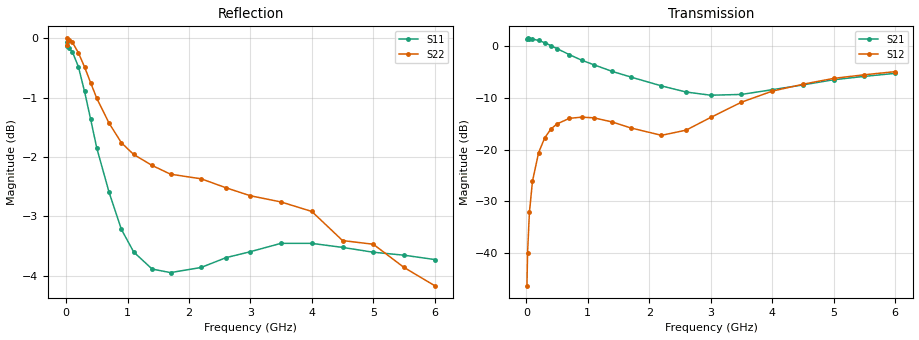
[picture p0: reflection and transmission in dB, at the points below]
! Infineon Technologies  Discrete & RF Semiconductors
! BFS17W
! Si NPN RF Bipolar Junction Transistor in SOT323
! VCE = 2 V  IC = 0.3 mA
! Common Emitter S-Parameters:  August  1999
# GHz  S  MA  R  50
!  f  S11  S21  S12  S22
! GHz  MAG  ANG  MAG  ANG  MAG  ANG  MAG  ANG
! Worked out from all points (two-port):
!   36 points, 10 MHz to 6 GHz, reference 50 ohm
!   highest |S21| = 1.58 dB at 20 MHz (marker M1); lowest = -9.4 dB at 3 GHz (marker M2)
!   |S21| within 3 dB of the highest: start of sweep to 671.9 MHz
!   lowest |S11| = -3.9 dB at 1.7 GHz (marker M3), VSWR 4.48, Z = 11.2 - j2.49 ohm
!   |S11| at or under -10 dB: nowhere
!   |S22| runs from -4.2 to 0.0 dB; largest |S21 - S12| = 1.2
!   S11 on the Smith chart (normalised r, x): 10 MHz: 27, -54; 300 MHz: 0.27, -2.04; 700 MHz: 0.24, -0.76; 1.4 GHz: 0.23, -0.19; 3 GHz: 0.24, +0.39; 6 GHz: 0.49, +1.09
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0.01  0.9852 -1.7  1.192 179.3  0.0048 86.8  0.9999 -0.1
0.02  0.9938 -3.8  1.199 176.9  0.0099 91.1  0.988 -1.1
0.05  0.9806 -9.1  1.195 172.2  0.0246 84.7  0.9971 -2.8
0.1  0.9746 -17.7  1.182 164.7  0.0494 79.0  0.9929 -5.6
0.2  0.9465 -35.4  1.144 149.2  0.0936 68.1  0.9723 -10.9
0.3  0.9022 -51.6  1.087 135.1  0.1304 58.2  0.946 -15.6
0.4  0.8545 -66.5  1.019 121.9  0.1585 49.4  0.9174 -19.8
0.5  0.808 -80.1  0.954 110.6  0.1776 42.0  0.89 -23.4
0.7  0.7418 -103.5  0.834 91.3  0.2012 30.8  0.8482 -29.8
0.9  0.6904 -122.5  0.737 76.2  0.2065 22.4  0.8167 -35.7
1.1  0.6608 -138.5  0.665 63.7  0.2035 16.7  0.7983 -41.5
1.4  0.6393 -157.9  0.573 49.4  0.1853 11.9  0.7815 -50.5
1.7  0.6349 -174.0  0.506 39.0  0.1624 12.7  0.7684 -60.1
2.2  0.6413 164.0  0.415 28.7  0.1377 28.9  0.7615 -76.4
2.6  0.6535 149.0  0.362 26.5  0.1545 47.8  0.7485 -90.0
3  0.6612 135.6  0.337 29.3  0.2051 57.6  0.7369 -103.1
3.5  0.672 121.1  0.343 34.2  0.2882 58.5  0.7281 -119.9
4  0.6719 109.0  0.381 36.3  0.3688 53.1  0.7148 -137.2
4.5  0.6667 98.5  0.424 35.2  0.4305 46.2  0.6756 -152.8
5  0.6605 90.6  0.476 31.8  0.4905 39.5  0.6708 -166.0
5.5  0.6567 83.9  0.513 27.7  0.532 33.0  0.6413 -179.5
6  0.6512 78.6  0.549 23.1  0.5701 26.9  0.619 168.7
